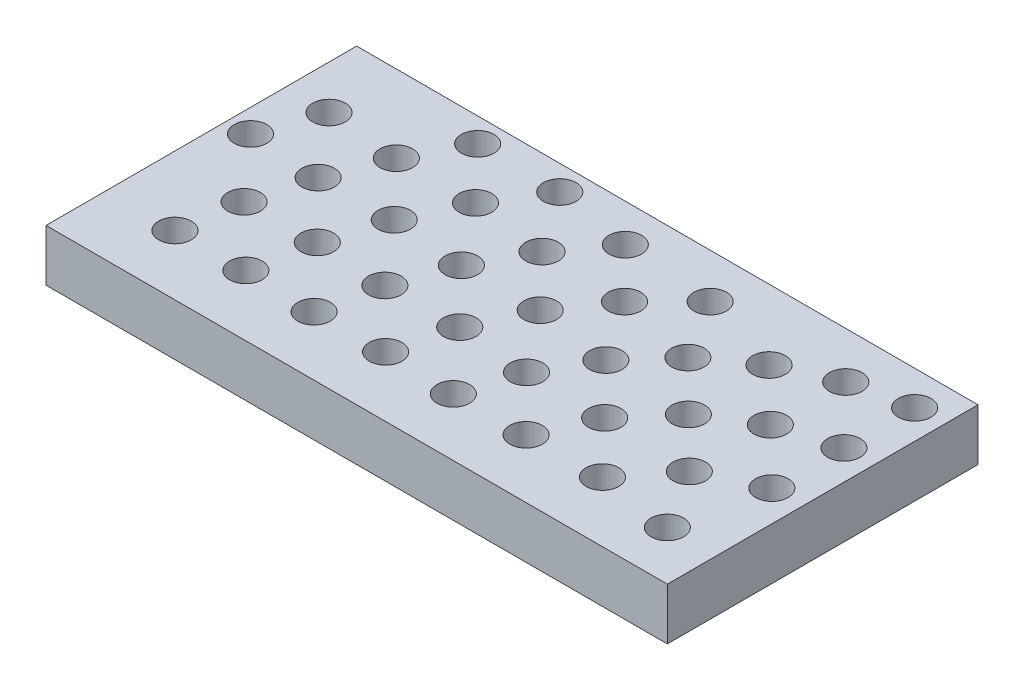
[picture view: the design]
ISO-10303-21;
HEADER;
FILE_DESCRIPTION(('STEP AP214'),'2;1');
FILE_NAME('part.step','',(''),(''),'','','');
FILE_SCHEMA(('AUTOMOTIVE_DESIGN { 1 0 10303 214 1 1 1 1 }'));
ENDSEC;
DATA;
#1=APPLICATION_CONTEXT('core data for automotive mechanical design processes');
#2=APPLICATION_PROTOCOL_DEFINITION('international standard','automotive_design',2000,#1);
#3=PRODUCT_CONTEXT('',#1,'mechanical');
#4=PRODUCT('Part','Part','',(#3));
#5=PRODUCT_RELATED_PRODUCT_CATEGORY('part','',(#4));
#6=PRODUCT_DEFINITION_FORMATION('','',#4);
#7=PRODUCT_DEFINITION_CONTEXT('part definition',#1,'design');
#8=PRODUCT_DEFINITION('design','',#6,#7);
#9=PRODUCT_DEFINITION_SHAPE('','',#8);
#10=(LENGTH_UNIT() NAMED_UNIT(*) SI_UNIT(.MILLI.,.METRE.));
#11=(NAMED_UNIT(*) PLANE_ANGLE_UNIT() SI_UNIT($,.RADIAN.));
#12=(NAMED_UNIT(*) SI_UNIT($,.STERADIAN.) SOLID_ANGLE_UNIT());
#13=UNCERTAINTY_MEASURE_WITH_UNIT(LENGTH_MEASURE(1.E-05),#10,'distance_accuracy_value','');
#14=(GEOMETRIC_REPRESENTATION_CONTEXT(3) GLOBAL_UNCERTAINTY_ASSIGNED_CONTEXT((#13)) GLOBAL_UNIT_ASSIGNED_CONTEXT((#10,
#11,#12)) REPRESENTATION_CONTEXT('',''));
#15=CARTESIAN_POINT('',(0.,0.,0.));
#16=DIRECTION('',(0.,0.,1.));
#17=DIRECTION('',(1.,0.,0.));
#18=AXIS2_PLACEMENT_3D('',#15,#16,#17);
#19=CARTESIAN_POINT('',(-76.2,12.7,-38.1));
#20=DIRECTION('',(1.,0.,0.));
#21=DIRECTION('',(0.,0.,-1.));
#22=AXIS2_PLACEMENT_3D('',#19,#20,#21);
#23=PLANE('',#22);
#24=DIRECTION('',(0.,0.,1.));
#25=VECTOR('',#24,1.);
#26=CARTESIAN_POINT('',(-76.2,0.,-38.1));
#27=LINE('',#26,#25);
#28=CARTESIAN_POINT('',(-76.2,0.,-38.1));
#29=VERTEX_POINT('',#28);
#30=CARTESIAN_POINT('',(-76.2,0.,38.1));
#31=VERTEX_POINT('',#30);
#32=EDGE_CURVE('E96',#29,#31,#27,.T.);
#33=ORIENTED_EDGE('',*,*,#32,.T.);
#34=DIRECTION('',(0.,-1.,0.));
#35=VECTOR('',#34,1.);
#36=CARTESIAN_POINT('',(-76.2,12.7,38.1));
#37=LINE('',#36,#35);
#38=CARTESIAN_POINT('',(-76.2,12.7,38.1));
#39=VERTEX_POINT('',#38);
#40=EDGE_CURVE('E12',#39,#31,#37,.T.);
#41=ORIENTED_EDGE('',*,*,#40,.F.);
#42=DIRECTION('',(0.,0.,1.));
#43=VECTOR('',#42,1.);
#44=CARTESIAN_POINT('',(-76.2,12.7,-38.1));
#45=LINE('',#44,#43);
#46=CARTESIAN_POINT('',(-76.2,12.7,-38.1));
#47=VERTEX_POINT('',#46);
#48=EDGE_CURVE('E84',#47,#39,#45,.T.);
#49=ORIENTED_EDGE('',*,*,#48,.F.);
#50=DIRECTION('',(0.,-1.,0.));
#51=VECTOR('',#50,1.);
#52=CARTESIAN_POINT('',(-76.2,12.7,-38.1));
#53=LINE('',#52,#51);
#54=EDGE_CURVE('E92',#47,#29,#53,.T.);
#55=ORIENTED_EDGE('',*,*,#54,.T.);
#56=EDGE_LOOP('',(#33,#41,#49,#55));
#57=FACE_BOUND('',#56,.T.);
#58=ADVANCED_FACE('F33',(#57),#23,.F.);
#59=CARTESIAN_POINT('',(-76.2,12.7,38.1));
#60=DIRECTION('',(0.,0.,-1.));
#61=DIRECTION('',(-1.,0.,0.));
#62=AXIS2_PLACEMENT_3D('',#59,#60,#61);
#63=PLANE('',#62);
#64=DIRECTION('',(1.,0.,0.));
#65=VECTOR('',#64,1.);
#66=CARTESIAN_POINT('',(-76.2,0.,38.1));
#67=LINE('',#66,#65);
#68=CARTESIAN_POINT('',(76.2,0.,38.1));
#69=VERTEX_POINT('',#68);
#70=EDGE_CURVE('E88',#31,#69,#67,.T.);
#71=ORIENTED_EDGE('',*,*,#70,.T.);
#72=DIRECTION('',(0.,-1.,0.));
#73=VECTOR('',#72,1.);
#74=CARTESIAN_POINT('',(76.2,12.7,38.1));
#75=LINE('',#74,#73);
#76=CARTESIAN_POINT('',(76.2,12.7,38.1));
#77=VERTEX_POINT('',#76);
#78=EDGE_CURVE('E41',#77,#69,#75,.T.);
#79=ORIENTED_EDGE('',*,*,#78,.F.);
#80=DIRECTION('',(1.,0.,0.));
#81=VECTOR('',#80,1.);
#82=CARTESIAN_POINT('',(-76.2,12.7,38.1));
#83=LINE('',#82,#81);
#84=EDGE_CURVE('E79',#39,#77,#83,.T.);
#85=ORIENTED_EDGE('',*,*,#84,.F.);
#86=ORIENTED_EDGE('',*,*,#40,.T.);
#87=EDGE_LOOP('',(#71,#79,#85,#86));
#88=FACE_BOUND('',#87,.T.);
#89=ADVANCED_FACE('F87',(#88),#63,.F.);
#90=CARTESIAN_POINT('',(76.2,12.7,-38.1));
#91=DIRECTION('',(-1.,0.,0.));
#92=DIRECTION('',(0.,0.,1.));
#93=AXIS2_PLACEMENT_3D('',#90,#91,#92);
#94=PLANE('',#93);
#95=DIRECTION('',(0.,0.,-1.));
#96=VECTOR('',#95,1.);
#97=CARTESIAN_POINT('',(76.2,0.,-38.1));
#98=LINE('',#97,#96);
#99=CARTESIAN_POINT('',(76.2,0.,-38.1));
#100=VERTEX_POINT('',#99);
#101=EDGE_CURVE('E66',#69,#100,#98,.T.);
#102=ORIENTED_EDGE('',*,*,#101,.T.);
#103=DIRECTION('',(0.,-1.,0.));
#104=VECTOR('',#103,1.);
#105=CARTESIAN_POINT('',(76.2,12.7,-38.1));
#106=LINE('',#105,#104);
#107=CARTESIAN_POINT('',(76.2,12.7,-38.1));
#108=VERTEX_POINT('',#107);
#109=EDGE_CURVE('E89',#108,#100,#106,.T.);
#110=ORIENTED_EDGE('',*,*,#109,.F.);
#111=DIRECTION('',(0.,0.,-1.));
#112=VECTOR('',#111,1.);
#113=CARTESIAN_POINT('',(76.2,12.7,-38.1));
#114=LINE('',#113,#112);
#115=EDGE_CURVE('E82',#77,#108,#114,.T.);
#116=ORIENTED_EDGE('',*,*,#115,.F.);
#117=ORIENTED_EDGE('',*,*,#78,.T.);
#118=EDGE_LOOP('',(#102,#110,#116,#117));
#119=FACE_BOUND('',#118,.T.);
#120=ADVANCED_FACE('F90',(#119),#94,.F.);
#121=CARTESIAN_POINT('',(-76.2,12.7,-38.1));
#122=DIRECTION('',(0.,0.,1.));
#123=DIRECTION('',(1.,0.,0.));
#124=AXIS2_PLACEMENT_3D('',#121,#122,#123);
#125=PLANE('',#124);
#126=DIRECTION('',(-1.,0.,0.));
#127=VECTOR('',#126,1.);
#128=CARTESIAN_POINT('',(-76.2,0.,-38.1));
#129=LINE('',#128,#127);
#130=EDGE_CURVE('E72',#100,#29,#129,.T.);
#131=ORIENTED_EDGE('',*,*,#130,.T.);
#132=ORIENTED_EDGE('',*,*,#54,.F.);
#133=DIRECTION('',(-1.,0.,0.));
#134=VECTOR('',#133,1.);
#135=CARTESIAN_POINT('',(-76.2,12.7,-38.1));
#136=LINE('',#135,#134);
#137=EDGE_CURVE('E49',#108,#47,#136,.T.);
#138=ORIENTED_EDGE('',*,*,#137,.F.);
#139=ORIENTED_EDGE('',*,*,#109,.T.);
#140=EDGE_LOOP('',(#131,#132,#138,#139));
#141=FACE_BOUND('',#140,.T.);
#142=ADVANCED_FACE('F104',(#141),#125,.F.);
#143=CARTESIAN_POINT('',(-76.2,12.7,38.1));
#144=DIRECTION('',(0.,1.,0.));
#145=DIRECTION('',(0.,0.,1.));
#146=AXIS2_PLACEMENT_3D('',#143,#144,#145);
#147=PLANE('',#146);
#148=CARTESIAN_POINT('',(-65.4765030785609,12.7,-20.5843290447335));
#149=DIRECTION('',(0.,1.,0.));
#150=DIRECTION('',(1.,0.,0.));
#151=AXIS2_PLACEMENT_3D('',#148,#149,#150);
#152=CIRCLE('',#151,4.);
#153=CARTESIAN_POINT('',(-61.4765030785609,12.7,-20.5843290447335));
#154=VERTEX_POINT('',#153);
#155=EDGE_CURVE('E332',#154,#154,#152,.T.);
#156=ORIENTED_EDGE('',*,*,#155,.F.);
#157=EDGE_LOOP('',(#156));
#158=FACE_BOUND('',#157,.T.);
#159=CARTESIAN_POINT('',(-70.546362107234,12.7,-6.41502227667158));
#160=DIRECTION('',(0.,1.,0.));
#161=DIRECTION('',(1.,0.,0.));
#162=AXIS2_PLACEMENT_3D('',#159,#160,#161);
#163=CIRCLE('',#162,4.);
#164=CARTESIAN_POINT('',(-66.546362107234,12.7,-6.41502227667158));
#165=VERTEX_POINT('',#164);
#166=EDGE_CURVE('E326',#165,#165,#163,.T.);
#167=ORIENTED_EDGE('',*,*,#166,.F.);
#168=EDGE_LOOP('',(#167));
#169=FACE_BOUND('',#168,.T.);
#170=CARTESIAN_POINT('',(-40.5988048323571,12.7,-32.175509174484));
#171=DIRECTION('',(0.,1.,0.));
#172=DIRECTION('',(1.,0.,0.));
#173=AXIS2_PLACEMENT_3D('',#170,#171,#172);
#174=CIRCLE('',#173,4.);
#175=CARTESIAN_POINT('',(-36.5988048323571,12.7,-32.175509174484));
#176=VERTEX_POINT('',#175);
#177=EDGE_CURVE('E320',#176,#176,#174,.T.);
#178=ORIENTED_EDGE('',*,*,#177,.F.);
#179=EDGE_LOOP('',(#178));
#180=FACE_BOUND('',#179,.T.);
#181=CARTESIAN_POINT('',(-47.5122443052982,12.7,-19.13537899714));
#182=DIRECTION('',(0.,1.,0.));
#183=DIRECTION('',(1.,0.,0.));
#184=AXIS2_PLACEMENT_3D('',#181,#182,#183);
#185=CIRCLE('',#184,4.);
#186=CARTESIAN_POINT('',(-43.5122443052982,12.7,-19.13537899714));
#187=VERTEX_POINT('',#186);
#188=EDGE_CURVE('E314',#187,#187,#185,.T.);
#189=ORIENTED_EDGE('',*,*,#188,.F.);
#190=EDGE_LOOP('',(#189));
#191=FACE_BOUND('',#190,.T.);
#192=CARTESIAN_POINT('',(-52.9752708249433,12.7,-5.42421633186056));
#193=DIRECTION('',(0.,1.,0.));
#194=DIRECTION('',(1.,0.,0.));
#195=AXIS2_PLACEMENT_3D('',#192,#193,#194);
#196=CIRCLE('',#195,4.);
#197=CARTESIAN_POINT('',(-48.9752708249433,12.7,-5.42421633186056));
#198=VERTEX_POINT('',#197);
#199=EDGE_CURVE('E308',#198,#198,#196,.T.);
#200=ORIENTED_EDGE('',*,*,#199,.F.);
#201=EDGE_LOOP('',(#200));
#202=FACE_BOUND('',#201,.T.);
#203=CARTESIAN_POINT('',(-56.9238354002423,12.7,8.79722797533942));
#204=DIRECTION('',(0.,1.,0.));
#205=DIRECTION('',(1.,0.,0.));
#206=AXIS2_PLACEMENT_3D('',#203,#204,#205);
#207=CIRCLE('',#206,4.);
#208=CARTESIAN_POINT('',(-52.9238354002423,12.7,8.79722797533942));
#209=VERTEX_POINT('',#208);
#210=EDGE_CURVE('E302',#209,#209,#207,.T.);
#211=ORIENTED_EDGE('',*,*,#210,.F.);
#212=EDGE_LOOP('',(#211));
#213=FACE_BOUND('',#212,.T.);
#214=CARTESIAN_POINT('',(-59.3116447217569,12.7,23.3622204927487));
#215=DIRECTION('',(0.,1.,0.));
#216=DIRECTION('',(1.,0.,0.));
#217=AXIS2_PLACEMENT_3D('',#214,#215,#216);
#218=CIRCLE('',#217,4.);
#219=CARTESIAN_POINT('',(-55.3116447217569,12.7,23.3622204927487));
#220=VERTEX_POINT('',#219);
#221=EDGE_CURVE('E296',#220,#220,#218,.T.);
#222=ORIENTED_EDGE('',*,*,#221,.F.);
#223=EDGE_LOOP('',(#222));
#224=FACE_BOUND('',#223,.T.);
#225=CARTESIAN_POINT('',(-20.2929664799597,12.7,-32.0062438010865));
#226=DIRECTION('',(0.,1.,0.));
#227=DIRECTION('',(1.,0.,0.));
#228=AXIS2_PLACEMENT_3D('',#225,#226,#227);
#229=CIRCLE('',#228,4.);
#230=CARTESIAN_POINT('',(-16.2929664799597,12.7,-32.0062438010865));
#231=VERTEX_POINT('',#230);
#232=EDGE_CURVE('E290',#231,#231,#229,.T.);
#233=ORIENTED_EDGE('',*,*,#232,.F.);
#234=EDGE_LOOP('',(#233));
#235=FACE_BOUND('',#234,.T.);
#236=CARTESIAN_POINT('',(-28.3187328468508,12.7,-19.3596596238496));
#237=DIRECTION('',(0.,1.,0.));
#238=DIRECTION('',(1.,0.,0.));
#239=AXIS2_PLACEMENT_3D('',#236,#237,#238);
#240=CIRCLE('',#239,4.);
#241=CARTESIAN_POINT('',(-24.3187328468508,12.7,-19.3596596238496));
#242=VERTEX_POINT('',#241);
#243=EDGE_CURVE('E284',#242,#242,#240,.T.);
#244=ORIENTED_EDGE('',*,*,#243,.F.);
#245=EDGE_LOOP('',(#244));
#246=FACE_BOUND('',#245,.T.);
#247=CARTESIAN_POINT('',(-34.6961763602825,12.7,-5.80690228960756));
#248=DIRECTION('',(0.,1.,0.));
#249=DIRECTION('',(1.,0.,0.));
#250=AXIS2_PLACEMENT_3D('',#247,#248,#249);
#251=CIRCLE('',#250,4.);
#252=CARTESIAN_POINT('',(-30.6961763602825,12.7,-5.80690228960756));
#253=VERTEX_POINT('',#252);
#254=EDGE_CURVE('E278',#253,#253,#251,.T.);
#255=ORIENTED_EDGE('',*,*,#254,.F.);
#256=EDGE_LOOP('',(#255));
#257=FACE_BOUND('',#256,.T.);
#258=CARTESIAN_POINT('',(-39.3247209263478,12.7,8.4382931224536));
#259=DIRECTION('',(0.,1.,0.));
#260=DIRECTION('',(1.,0.,0.));
#261=AXIS2_PLACEMENT_3D('',#258,#259,#260);
#262=CIRCLE('',#261,4.);
#263=CARTESIAN_POINT('',(-35.3247209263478,12.7,8.4382931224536));
#264=VERTEX_POINT('',#263);
#265=EDGE_CURVE('E272',#264,#264,#262,.T.);
#266=ORIENTED_EDGE('',*,*,#265,.F.);
#267=EDGE_LOOP('',(#266));
#268=FACE_BOUND('',#267,.T.);
#269=CARTESIAN_POINT('',(-1.06256734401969,12.7,-28.8483957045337));
#270=DIRECTION('',(0.,1.,0.));
#271=DIRECTION('',(1.,0.,0.));
#272=AXIS2_PLACEMENT_3D('',#269,#270,#271);
#273=CIRCLE('',#272,4.);
#274=CARTESIAN_POINT('',(2.93743265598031,12.7,-28.8483957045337));
#275=VERTEX_POINT('',#274);
#276=EDGE_CURVE('E266',#275,#275,#273,.T.);
#277=ORIENTED_EDGE('',*,*,#276,.F.);
#278=EDGE_LOOP('',(#277));
#279=FACE_BOUND('',#278,.T.);
#280=CARTESIAN_POINT('',(-42.1313716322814,12.7,23.1512713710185));
#281=DIRECTION('',(0.,1.,0.));
#282=DIRECTION('',(1.,0.,0.));
#283=AXIS2_PLACEMENT_3D('',#280,#281,#282);
#284=CIRCLE('',#283,4.);
#285=CARTESIAN_POINT('',(-38.1313716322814,12.7,23.1512713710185));
#286=VERTEX_POINT('',#285);
#287=EDGE_CURVE('E260',#286,#286,#284,.T.);
#288=ORIENTED_EDGE('',*,*,#287,.F.);
#289=EDGE_LOOP('',(#288));
#290=FACE_BOUND('',#289,.T.);
#291=CARTESIAN_POINT('',(-9.80389591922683,12.7,-17.1713477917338));
#292=DIRECTION('',(0.,1.,0.));
#293=DIRECTION('',(1.,0.,0.));
#294=AXIS2_PLACEMENT_3D('',#291,#292,#293);
#295=CIRCLE('',#294,4.);
#296=CARTESIAN_POINT('',(-5.80389591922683,12.7,-17.1713477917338));
#297=VERTEX_POINT('',#296);
#298=EDGE_CURVE('E254',#297,#297,#295,.T.);
#299=ORIENTED_EDGE('',*,*,#298,.F.);
#300=EDGE_LOOP('',(#299));
#301=FACE_BOUND('',#300,.T.);
#302=CARTESIAN_POINT('',(-16.7944331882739,12.7,-4.36913462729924));
#303=DIRECTION('',(0.,1.,0.));
#304=DIRECTION('',(1.,0.,0.));
#305=AXIS2_PLACEMENT_3D('',#302,#303,#304);
#306=CIRCLE('',#305,4.);
#307=CARTESIAN_POINT('',(-12.7944331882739,12.7,-4.36913462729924));
#308=VERTEX_POINT('',#307);
#309=EDGE_CURVE('E248',#308,#308,#306,.T.);
#310=ORIENTED_EDGE('',*,*,#309,.F.);
#311=EDGE_LOOP('',(#310));
#312=FACE_BOUND('',#311,.T.);
#313=CARTESIAN_POINT('',(-21.8918719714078,12.7,9.29762764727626));
#314=DIRECTION('',(0.,1.,0.));
#315=DIRECTION('',(1.,0.,0.));
#316=AXIS2_PLACEMENT_3D('',#313,#314,#315);
#317=CIRCLE('',#316,4.);
#318=CARTESIAN_POINT('',(-17.8918719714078,12.7,9.29762764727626));
#319=VERTEX_POINT('',#318);
#320=EDGE_CURVE('E242',#319,#319,#317,.T.);
#321=ORIENTED_EDGE('',*,*,#320,.F.);
#322=EDGE_LOOP('',(#321));
#323=FACE_BOUND('',#322,.T.);
#324=CARTESIAN_POINT('',(-24.9924431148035,12.7,23.5507231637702));
#325=DIRECTION('',(0.,1.,0.));
#326=DIRECTION('',(1.,0.,0.));
#327=AXIS2_PLACEMENT_3D('',#324,#325,#326);
#328=CIRCLE('',#327,4.);
#329=CARTESIAN_POINT('',(-20.9924431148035,12.7,23.5507231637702));
#330=VERTEX_POINT('',#329);
#331=EDGE_CURVE('E236',#330,#330,#328,.T.);
#332=ORIENTED_EDGE('',*,*,#331,.F.);
#333=EDGE_LOOP('',(#332));
#334=FACE_BOUND('',#333,.T.);
#335=CARTESIAN_POINT('',(21.4382302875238,12.7,-27.1625357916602));
#336=DIRECTION('',(0.,1.,0.));
#337=DIRECTION('',(1.,0.,0.));
#338=AXIS2_PLACEMENT_3D('',#335,#336,#337);
#339=CIRCLE('',#338,4.);
#340=CARTESIAN_POINT('',(25.4382302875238,12.7,-27.1625357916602));
#341=VERTEX_POINT('',#340);
#342=EDGE_CURVE('E230',#341,#341,#339,.T.);
#343=ORIENTED_EDGE('',*,*,#342,.F.);
#344=EDGE_LOOP('',(#343));
#345=FACE_BOUND('',#344,.T.);
#346=CARTESIAN_POINT('',(10.9374642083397,12.7,-16.6617697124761));
#347=DIRECTION('',(0.,1.,0.));
#348=DIRECTION('',(1.,0.,0.));
#349=AXIS2_PLACEMENT_3D('',#346,#347,#348);
#350=CIRCLE('',#349,4.);
#351=CARTESIAN_POINT('',(14.9374642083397,12.7,-16.6617697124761));
#352=VERTEX_POINT('',#351);
#353=EDGE_CURVE('E224',#352,#352,#350,.T.);
#354=ORIENTED_EDGE('',*,*,#353,.F.);
#355=EDGE_LOOP('',(#354));
#356=FACE_BOUND('',#355,.T.);
#357=CARTESIAN_POINT('',(69.075825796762,12.7,-29.6819898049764));
#358=DIRECTION('',(0.,1.,0.));
#359=DIRECTION('',(1.,0.,0.));
#360=AXIS2_PLACEMENT_3D('',#357,#358,#359);
#361=CIRCLE('',#360,4.);
#362=CARTESIAN_POINT('',(73.0758257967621,12.7,-29.6819898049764));
#363=VERTEX_POINT('',#362);
#364=EDGE_CURVE('E218',#363,#363,#361,.T.);
#365=ORIENTED_EDGE('',*,*,#364,.F.);
#366=EDGE_LOOP('',(#365));
#367=FACE_BOUND('',#366,.T.);
#368=CARTESIAN_POINT('',(2.41966725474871,12.7,-4.49709497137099));
#369=DIRECTION('',(0.,1.,0.));
#370=DIRECTION('',(1.,0.,0.));
#371=AXIS2_PLACEMENT_3D('',#368,#369,#370);
#372=CIRCLE('',#371,4.);
#373=CARTESIAN_POINT('',(6.41966725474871,12.7,-4.49709497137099));
#374=VERTEX_POINT('',#373);
#375=EDGE_CURVE('E212',#374,#374,#372,.T.);
#376=ORIENTED_EDGE('',*,*,#375,.F.);
#377=EDGE_LOOP('',(#376));
#378=FACE_BOUND('',#377,.T.);
#379=CARTESIAN_POINT('',(55.1388379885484,12.7,-26.7195915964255));
#380=DIRECTION('',(0.,1.,0.));
#381=DIRECTION('',(1.,0.,0.));
#382=AXIS2_PLACEMENT_3D('',#379,#380,#381);
#383=CIRCLE('',#382,4.);
#384=CARTESIAN_POINT('',(59.1388379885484,12.7,-26.7195915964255));
#385=VERTEX_POINT('',#384);
#386=EDGE_CURVE('E206',#385,#385,#383,.T.);
#387=ORIENTED_EDGE('',*,*,#386,.F.);
#388=EDGE_LOOP('',(#387));
#389=FACE_BOUND('',#388,.T.);
#390=CARTESIAN_POINT('',(-3.85635162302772,12.7,8.96187094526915));
#391=DIRECTION('',(0.,1.,0.));
#392=DIRECTION('',(1.,0.,0.));
#393=AXIS2_PLACEMENT_3D('',#390,#391,#392);
#394=CIRCLE('',#393,4.);
#395=CARTESIAN_POINT('',(0.143648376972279,12.7,8.96187094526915));
#396=VERTEX_POINT('',#395);
#397=EDGE_CURVE('E200',#396,#396,#394,.T.);
#398=ORIENTED_EDGE('',*,*,#397,.F.);
#399=EDGE_LOOP('',(#398));
#400=FACE_BOUND('',#399,.T.);
#401=CARTESIAN_POINT('',(42.1223240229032,12.7,-20.924266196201));
#402=DIRECTION('',(0.,1.,0.));
#403=DIRECTION('',(1.,0.,0.));
#404=AXIS2_PLACEMENT_3D('',#401,#402,#403);
#405=CIRCLE('',#404,4.);
#406=CARTESIAN_POINT('',(46.1223240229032,12.7,-20.924266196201));
#407=VERTEX_POINT('',#406);
#408=EDGE_CURVE('E194',#407,#407,#405,.T.);
#409=ORIENTED_EDGE('',*,*,#408,.F.);
#410=EDGE_LOOP('',(#409));
#411=FACE_BOUND('',#410,.T.);
#412=CARTESIAN_POINT('',(-7.699898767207,12.7,23.3061841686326));
#413=DIRECTION('',(0.,1.,0.));
#414=DIRECTION('',(1.,0.,0.));
#415=AXIS2_PLACEMENT_3D('',#412,#413,#414);
#416=CIRCLE('',#415,4.);
#417=CARTESIAN_POINT('',(-3.699898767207,12.7,23.3061841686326));
#418=VERTEX_POINT('',#417);
#419=EDGE_CURVE('E188',#418,#418,#416,.T.);
#420=ORIENTED_EDGE('',*,*,#419,.F.);
#421=EDGE_LOOP('',(#420));
#422=FACE_BOUND('',#421,.T.);
#423=CARTESIAN_POINT('',(30.5951680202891,12.7,-12.5492971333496));
#424=DIRECTION('',(0.,1.,0.));
#425=DIRECTION('',(1.,0.,0.));
#426=AXIS2_PLACEMENT_3D('',#423,#424,#425);
#427=CIRCLE('',#426,4.);
#428=CARTESIAN_POINT('',(34.5951680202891,12.7,-12.5492971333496));
#429=VERTEX_POINT('',#428);
#430=EDGE_CURVE('E182',#429,#429,#427,.T.);
#431=ORIENTED_EDGE('',*,*,#430,.F.);
#432=EDGE_LOOP('',(#431));
#433=FACE_BOUND('',#432,.T.);
#434=CARTESIAN_POINT('',(21.0611620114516,12.7,-1.96071074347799));
#435=DIRECTION('',(0.,1.,0.));
#436=DIRECTION('',(1.,0.,0.));
#437=AXIS2_PLACEMENT_3D('',#434,#435,#436);
#438=CIRCLE('',#437,4.);
#439=CARTESIAN_POINT('',(25.0611620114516,12.7,-1.96071074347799));
#440=VERTEX_POINT('',#439);
#441=EDGE_CURVE('E176',#440,#440,#438,.T.);
#442=ORIENTED_EDGE('',*,*,#441,.F.);
#443=EDGE_LOOP('',(#442));
#444=FACE_BOUND('',#443,.T.);
#445=CARTESIAN_POINT('',(13.9369878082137,12.7,10.3787209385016));
#446=DIRECTION('',(0.,1.,0.));
#447=DIRECTION('',(1.,0.,0.));
#448=AXIS2_PLACEMENT_3D('',#445,#446,#447);
#449=CIRCLE('',#448,4.);
#450=CARTESIAN_POINT('',(17.9369878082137,12.7,10.3787209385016));
#451=VERTEX_POINT('',#450);
#452=EDGE_CURVE('E170',#451,#451,#449,.T.);
#453=ORIENTED_EDGE('',*,*,#452,.F.);
#454=EDGE_LOOP('',(#453));
#455=FACE_BOUND('',#454,.T.);
#456=CARTESIAN_POINT('',(9.53400600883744,12.7,23.9297055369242));
#457=DIRECTION('',(0.,1.,0.));
#458=DIRECTION('',(1.,0.,0.));
#459=AXIS2_PLACEMENT_3D('',#456,#457,#458);
#460=CIRCLE('',#459,4.);
#461=CARTESIAN_POINT('',(13.5340060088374,12.7,23.9297055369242));
#462=VERTEX_POINT('',#461);
#463=EDGE_CURVE('E164',#462,#462,#460,.T.);
#464=ORIENTED_EDGE('',*,*,#463,.F.);
#465=EDGE_LOOP('',(#464));
#466=FACE_BOUND('',#465,.T.);
#467=CARTESIAN_POINT('',(68.9253615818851,12.7,-12.4962215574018));
#468=DIRECTION('',(0.,1.,0.));
#469=DIRECTION('',(1.,0.,0.));
#470=AXIS2_PLACEMENT_3D('',#467,#468,#469);
#471=CIRCLE('',#470,4.);
#472=CARTESIAN_POINT('',(72.9253615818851,12.7,-12.4962215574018));
#473=VERTEX_POINT('',#472);
#474=EDGE_CURVE('E158',#473,#473,#471,.T.);
#475=ORIENTED_EDGE('',*,*,#474,.F.);
#476=EDGE_LOOP('',(#475));
#477=FACE_BOUND('',#476,.T.);
#478=CARTESIAN_POINT('',(54.9654326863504,12.7,-8.39721659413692));
#479=DIRECTION('',(0.,1.,0.));
#480=DIRECTION('',(1.,0.,0.));
#481=AXIS2_PLACEMENT_3D('',#478,#479,#480);
#482=CIRCLE('',#481,4.);
#483=CARTESIAN_POINT('',(58.9654326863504,12.7,-8.39721659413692));
#484=VERTEX_POINT('',#483);
#485=EDGE_CURVE('E152',#484,#484,#482,.T.);
#486=ORIENTED_EDGE('',*,*,#485,.F.);
#487=EDGE_LOOP('',(#486));
#488=FACE_BOUND('',#487,.T.);
#489=CARTESIAN_POINT('',(42.7258021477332,12.7,-0.531283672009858));
#490=DIRECTION('',(0.,1.,0.));
#491=DIRECTION('',(1.,0.,0.));
#492=AXIS2_PLACEMENT_3D('',#489,#490,#491);
#493=CIRCLE('',#492,4.);
#494=CARTESIAN_POINT('',(46.7258021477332,12.7,-0.531283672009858));
#495=VERTEX_POINT('',#494);
#496=EDGE_CURVE('E146',#495,#495,#493,.T.);
#497=ORIENTED_EDGE('',*,*,#496,.F.);
#498=EDGE_LOOP('',(#497));
#499=FACE_BOUND('',#498,.T.);
#500=CARTESIAN_POINT('',(33.1980520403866,12.7,10.4643261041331));
#501=DIRECTION('',(0.,1.,0.));
#502=DIRECTION('',(1.,0.,0.));
#503=AXIS2_PLACEMENT_3D('',#500,#501,#502);
#504=CIRCLE('',#503,4.);
#505=CARTESIAN_POINT('',(37.1980520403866,12.7,10.4643261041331));
#506=VERTEX_POINT('',#505);
#507=EDGE_CURVE('E140',#506,#506,#504,.T.);
#508=ORIENTED_EDGE('',*,*,#507,.F.);
#509=EDGE_LOOP('',(#508));
#510=FACE_BOUND('',#509,.T.);
#511=CARTESIAN_POINT('',(27.1540640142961,12.7,23.6988138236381));
#512=DIRECTION('',(0.,1.,0.));
#513=DIRECTION('',(1.,0.,0.));
#514=AXIS2_PLACEMENT_3D('',#511,#512,#513);
#515=CIRCLE('',#514,4.);
#516=CARTESIAN_POINT('',(31.1540640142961,12.7,23.6988138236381));
#517=VERTEX_POINT('',#516);
#518=EDGE_CURVE('E134',#517,#517,#515,.T.);
#519=ORIENTED_EDGE('',*,*,#518,.F.);
#520=EDGE_LOOP('',(#519));
#521=FACE_BOUND('',#520,.T.);
#522=CARTESIAN_POINT('',(68.6170037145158,12.7,4.87672250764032));
#523=DIRECTION('',(0.,1.,0.));
#524=DIRECTION('',(1.,0.,0.));
#525=AXIS2_PLACEMENT_3D('',#522,#523,#524);
#526=CIRCLE('',#525,4.);
#527=CARTESIAN_POINT('',(72.6170037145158,12.7,4.87672250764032));
#528=VERTEX_POINT('',#527);
#529=EDGE_CURVE('E128',#528,#528,#526,.T.);
#530=ORIENTED_EDGE('',*,*,#529,.F.);
#531=EDGE_LOOP('',(#530));
#532=FACE_BOUND('',#531,.T.);
#533=CARTESIAN_POINT('',(54.9529165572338,12.7,11.4570000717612));
#534=DIRECTION('',(0.,1.,0.));
#535=DIRECTION('',(1.,0.,0.));
#536=AXIS2_PLACEMENT_3D('',#533,#534,#535);
#537=CIRCLE('',#536,4.);
#538=CARTESIAN_POINT('',(58.9529165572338,12.7,11.4570000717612));
#539=VERTEX_POINT('',#538);
#540=EDGE_CURVE('E122',#539,#539,#537,.T.);
#541=ORIENTED_EDGE('',*,*,#540,.F.);
#542=EDGE_LOOP('',(#541));
#543=FACE_BOUND('',#542,.T.);
#544=CARTESIAN_POINT('',(45.4970748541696,12.7,23.3142505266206));
#545=DIRECTION('',(0.,1.,0.));
#546=DIRECTION('',(1.,0.,0.));
#547=AXIS2_PLACEMENT_3D('',#544,#545,#546);
#548=CIRCLE('',#547,4.);
#549=CARTESIAN_POINT('',(49.4970748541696,12.7,23.3142505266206));
#550=VERTEX_POINT('',#549);
#551=EDGE_CURVE('E116',#550,#550,#548,.T.);
#552=ORIENTED_EDGE('',*,*,#551,.F.);
#553=EDGE_LOOP('',(#552));
#554=FACE_BOUND('',#553,.T.);
#555=CARTESIAN_POINT('',(64.1517221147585,12.7,26.0517221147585));
#556=DIRECTION('',(0.,1.,0.));
#557=DIRECTION('',(1.,0.,0.));
#558=AXIS2_PLACEMENT_3D('',#555,#556,#557);
#559=CIRCLE('',#558,4.);
#560=CARTESIAN_POINT('',(68.1517221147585,12.7,26.0517221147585));
#561=VERTEX_POINT('',#560);
#562=EDGE_CURVE('E110',#561,#561,#559,.T.);
#563=ORIENTED_EDGE('',*,*,#562,.F.);
#564=EDGE_LOOP('',(#563));
#565=FACE_BOUND('',#564,.T.);
#566=ORIENTED_EDGE('',*,*,#48,.T.);
#567=ORIENTED_EDGE('',*,*,#84,.T.);
#568=ORIENTED_EDGE('',*,*,#115,.T.);
#569=ORIENTED_EDGE('',*,*,#137,.T.);
#570=EDGE_LOOP('',(#566,#567,#568,#569));
#571=FACE_BOUND('',#570,.T.);
#572=ADVANCED_FACE('F80',(#158,#169,#180,#191,#202,#213,#224,#235,#246,#257,#268,#279,#290,#301,
#312,#323,#334,#345,#356,#367,#378,#389,#400,#411,#422,#433,#444,#455,#466,#477,#488,#499,#510,
#521,#532,#543,#554,#565,#571),#147,.T.);
#573=CARTESIAN_POINT('',(-76.2,0.,38.1));
#574=DIRECTION('',(0.,1.,0.));
#575=DIRECTION('',(0.,0.,1.));
#576=AXIS2_PLACEMENT_3D('',#573,#574,#575);
#577=PLANE('',#576);
#578=CARTESIAN_POINT('',(-65.4765030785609,0.,-20.5843290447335));
#579=DIRECTION('',(0.,1.,0.));
#580=DIRECTION('',(1.,0.,0.));
#581=AXIS2_PLACEMENT_3D('',#578,#579,#580);
#582=CIRCLE('',#581,4.);
#583=CARTESIAN_POINT('',(-61.4765030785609,0.,-20.5843290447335));
#584=VERTEX_POINT('',#583);
#585=EDGE_CURVE('E329',#584,#584,#582,.T.);
#586=ORIENTED_EDGE('',*,*,#585,.T.);
#587=EDGE_LOOP('',(#586));
#588=FACE_BOUND('',#587,.T.);
#589=CARTESIAN_POINT('',(-70.546362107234,0.,-6.41502227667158));
#590=DIRECTION('',(0.,1.,0.));
#591=DIRECTION('',(1.,0.,0.));
#592=AXIS2_PLACEMENT_3D('',#589,#590,#591);
#593=CIRCLE('',#592,4.);
#594=CARTESIAN_POINT('',(-66.546362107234,0.,-6.41502227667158));
#595=VERTEX_POINT('',#594);
#596=EDGE_CURVE('E323',#595,#595,#593,.T.);
#597=ORIENTED_EDGE('',*,*,#596,.T.);
#598=EDGE_LOOP('',(#597));
#599=FACE_BOUND('',#598,.T.);
#600=CARTESIAN_POINT('',(-40.5988048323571,0.,-32.175509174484));
#601=DIRECTION('',(0.,1.,0.));
#602=DIRECTION('',(1.,0.,0.));
#603=AXIS2_PLACEMENT_3D('',#600,#601,#602);
#604=CIRCLE('',#603,4.);
#605=CARTESIAN_POINT('',(-36.5988048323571,0.,-32.175509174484));
#606=VERTEX_POINT('',#605);
#607=EDGE_CURVE('E317',#606,#606,#604,.T.);
#608=ORIENTED_EDGE('',*,*,#607,.T.);
#609=EDGE_LOOP('',(#608));
#610=FACE_BOUND('',#609,.T.);
#611=CARTESIAN_POINT('',(-47.5122443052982,0.,-19.13537899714));
#612=DIRECTION('',(0.,1.,0.));
#613=DIRECTION('',(1.,0.,0.));
#614=AXIS2_PLACEMENT_3D('',#611,#612,#613);
#615=CIRCLE('',#614,4.);
#616=CARTESIAN_POINT('',(-43.5122443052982,0.,-19.13537899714));
#617=VERTEX_POINT('',#616);
#618=EDGE_CURVE('E311',#617,#617,#615,.T.);
#619=ORIENTED_EDGE('',*,*,#618,.T.);
#620=EDGE_LOOP('',(#619));
#621=FACE_BOUND('',#620,.T.);
#622=CARTESIAN_POINT('',(-52.9752708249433,0.,-5.42421633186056));
#623=DIRECTION('',(0.,1.,0.));
#624=DIRECTION('',(1.,0.,0.));
#625=AXIS2_PLACEMENT_3D('',#622,#623,#624);
#626=CIRCLE('',#625,4.);
#627=CARTESIAN_POINT('',(-48.9752708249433,0.,-5.42421633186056));
#628=VERTEX_POINT('',#627);
#629=EDGE_CURVE('E305',#628,#628,#626,.T.);
#630=ORIENTED_EDGE('',*,*,#629,.T.);
#631=EDGE_LOOP('',(#630));
#632=FACE_BOUND('',#631,.T.);
#633=CARTESIAN_POINT('',(-56.9238354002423,0.,8.79722797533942));
#634=DIRECTION('',(0.,1.,0.));
#635=DIRECTION('',(1.,0.,0.));
#636=AXIS2_PLACEMENT_3D('',#633,#634,#635);
#637=CIRCLE('',#636,4.);
#638=CARTESIAN_POINT('',(-52.9238354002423,0.,8.79722797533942));
#639=VERTEX_POINT('',#638);
#640=EDGE_CURVE('E299',#639,#639,#637,.T.);
#641=ORIENTED_EDGE('',*,*,#640,.T.);
#642=EDGE_LOOP('',(#641));
#643=FACE_BOUND('',#642,.T.);
#644=CARTESIAN_POINT('',(-59.3116447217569,0.,23.3622204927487));
#645=DIRECTION('',(0.,1.,0.));
#646=DIRECTION('',(1.,0.,0.));
#647=AXIS2_PLACEMENT_3D('',#644,#645,#646);
#648=CIRCLE('',#647,4.);
#649=CARTESIAN_POINT('',(-55.3116447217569,0.,23.3622204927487));
#650=VERTEX_POINT('',#649);
#651=EDGE_CURVE('E293',#650,#650,#648,.T.);
#652=ORIENTED_EDGE('',*,*,#651,.T.);
#653=EDGE_LOOP('',(#652));
#654=FACE_BOUND('',#653,.T.);
#655=CARTESIAN_POINT('',(-20.2929664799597,0.,-32.0062438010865));
#656=DIRECTION('',(0.,1.,0.));
#657=DIRECTION('',(1.,0.,0.));
#658=AXIS2_PLACEMENT_3D('',#655,#656,#657);
#659=CIRCLE('',#658,4.);
#660=CARTESIAN_POINT('',(-16.2929664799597,0.,-32.0062438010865));
#661=VERTEX_POINT('',#660);
#662=EDGE_CURVE('E287',#661,#661,#659,.T.);
#663=ORIENTED_EDGE('',*,*,#662,.T.);
#664=EDGE_LOOP('',(#663));
#665=FACE_BOUND('',#664,.T.);
#666=CARTESIAN_POINT('',(-28.3187328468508,0.,-19.3596596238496));
#667=DIRECTION('',(0.,1.,0.));
#668=DIRECTION('',(1.,0.,0.));
#669=AXIS2_PLACEMENT_3D('',#666,#667,#668);
#670=CIRCLE('',#669,4.);
#671=CARTESIAN_POINT('',(-24.3187328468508,0.,-19.3596596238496));
#672=VERTEX_POINT('',#671);
#673=EDGE_CURVE('E281',#672,#672,#670,.T.);
#674=ORIENTED_EDGE('',*,*,#673,.T.);
#675=EDGE_LOOP('',(#674));
#676=FACE_BOUND('',#675,.T.);
#677=CARTESIAN_POINT('',(-34.6961763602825,0.,-5.80690228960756));
#678=DIRECTION('',(0.,1.,0.));
#679=DIRECTION('',(1.,0.,0.));
#680=AXIS2_PLACEMENT_3D('',#677,#678,#679);
#681=CIRCLE('',#680,4.);
#682=CARTESIAN_POINT('',(-30.6961763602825,0.,-5.80690228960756));
#683=VERTEX_POINT('',#682);
#684=EDGE_CURVE('E275',#683,#683,#681,.T.);
#685=ORIENTED_EDGE('',*,*,#684,.T.);
#686=EDGE_LOOP('',(#685));
#687=FACE_BOUND('',#686,.T.);
#688=CARTESIAN_POINT('',(-39.3247209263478,0.,8.4382931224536));
#689=DIRECTION('',(0.,1.,0.));
#690=DIRECTION('',(1.,0.,0.));
#691=AXIS2_PLACEMENT_3D('',#688,#689,#690);
#692=CIRCLE('',#691,4.);
#693=CARTESIAN_POINT('',(-35.3247209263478,0.,8.4382931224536));
#694=VERTEX_POINT('',#693);
#695=EDGE_CURVE('E269',#694,#694,#692,.T.);
#696=ORIENTED_EDGE('',*,*,#695,.T.);
#697=EDGE_LOOP('',(#696));
#698=FACE_BOUND('',#697,.T.);
#699=CARTESIAN_POINT('',(-1.06256734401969,0.,-28.8483957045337));
#700=DIRECTION('',(0.,1.,0.));
#701=DIRECTION('',(1.,0.,0.));
#702=AXIS2_PLACEMENT_3D('',#699,#700,#701);
#703=CIRCLE('',#702,4.);
#704=CARTESIAN_POINT('',(2.93743265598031,0.,-28.8483957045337));
#705=VERTEX_POINT('',#704);
#706=EDGE_CURVE('E263',#705,#705,#703,.T.);
#707=ORIENTED_EDGE('',*,*,#706,.T.);
#708=EDGE_LOOP('',(#707));
#709=FACE_BOUND('',#708,.T.);
#710=CARTESIAN_POINT('',(-42.1313716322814,0.,23.1512713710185));
#711=DIRECTION('',(0.,1.,0.));
#712=DIRECTION('',(1.,0.,0.));
#713=AXIS2_PLACEMENT_3D('',#710,#711,#712);
#714=CIRCLE('',#713,4.);
#715=CARTESIAN_POINT('',(-38.1313716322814,0.,23.1512713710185));
#716=VERTEX_POINT('',#715);
#717=EDGE_CURVE('E257',#716,#716,#714,.T.);
#718=ORIENTED_EDGE('',*,*,#717,.T.);
#719=EDGE_LOOP('',(#718));
#720=FACE_BOUND('',#719,.T.);
#721=CARTESIAN_POINT('',(-9.80389591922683,0.,-17.1713477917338));
#722=DIRECTION('',(0.,1.,0.));
#723=DIRECTION('',(1.,0.,0.));
#724=AXIS2_PLACEMENT_3D('',#721,#722,#723);
#725=CIRCLE('',#724,4.);
#726=CARTESIAN_POINT('',(-5.80389591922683,0.,-17.1713477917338));
#727=VERTEX_POINT('',#726);
#728=EDGE_CURVE('E251',#727,#727,#725,.T.);
#729=ORIENTED_EDGE('',*,*,#728,.T.);
#730=EDGE_LOOP('',(#729));
#731=FACE_BOUND('',#730,.T.);
#732=CARTESIAN_POINT('',(-16.7944331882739,0.,-4.36913462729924));
#733=DIRECTION('',(0.,1.,0.));
#734=DIRECTION('',(1.,0.,0.));
#735=AXIS2_PLACEMENT_3D('',#732,#733,#734);
#736=CIRCLE('',#735,4.);
#737=CARTESIAN_POINT('',(-12.7944331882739,0.,-4.36913462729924));
#738=VERTEX_POINT('',#737);
#739=EDGE_CURVE('E245',#738,#738,#736,.T.);
#740=ORIENTED_EDGE('',*,*,#739,.T.);
#741=EDGE_LOOP('',(#740));
#742=FACE_BOUND('',#741,.T.);
#743=CARTESIAN_POINT('',(-21.8918719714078,0.,9.29762764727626));
#744=DIRECTION('',(0.,1.,0.));
#745=DIRECTION('',(1.,0.,0.));
#746=AXIS2_PLACEMENT_3D('',#743,#744,#745);
#747=CIRCLE('',#746,4.);
#748=CARTESIAN_POINT('',(-17.8918719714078,0.,9.29762764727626));
#749=VERTEX_POINT('',#748);
#750=EDGE_CURVE('E239',#749,#749,#747,.T.);
#751=ORIENTED_EDGE('',*,*,#750,.T.);
#752=EDGE_LOOP('',(#751));
#753=FACE_BOUND('',#752,.T.);
#754=CARTESIAN_POINT('',(-24.9924431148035,0.,23.5507231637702));
#755=DIRECTION('',(0.,1.,0.));
#756=DIRECTION('',(1.,0.,0.));
#757=AXIS2_PLACEMENT_3D('',#754,#755,#756);
#758=CIRCLE('',#757,4.);
#759=CARTESIAN_POINT('',(-20.9924431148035,0.,23.5507231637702));
#760=VERTEX_POINT('',#759);
#761=EDGE_CURVE('E233',#760,#760,#758,.T.);
#762=ORIENTED_EDGE('',*,*,#761,.T.);
#763=EDGE_LOOP('',(#762));
#764=FACE_BOUND('',#763,.T.);
#765=CARTESIAN_POINT('',(21.4382302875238,0.,-27.1625357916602));
#766=DIRECTION('',(0.,1.,0.));
#767=DIRECTION('',(1.,0.,0.));
#768=AXIS2_PLACEMENT_3D('',#765,#766,#767);
#769=CIRCLE('',#768,4.);
#770=CARTESIAN_POINT('',(25.4382302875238,0.,-27.1625357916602));
#771=VERTEX_POINT('',#770);
#772=EDGE_CURVE('E227',#771,#771,#769,.T.);
#773=ORIENTED_EDGE('',*,*,#772,.T.);
#774=EDGE_LOOP('',(#773));
#775=FACE_BOUND('',#774,.T.);
#776=CARTESIAN_POINT('',(10.9374642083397,0.,-16.6617697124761));
#777=DIRECTION('',(0.,1.,0.));
#778=DIRECTION('',(1.,0.,0.));
#779=AXIS2_PLACEMENT_3D('',#776,#777,#778);
#780=CIRCLE('',#779,4.);
#781=CARTESIAN_POINT('',(14.9374642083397,0.,-16.6617697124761));
#782=VERTEX_POINT('',#781);
#783=EDGE_CURVE('E221',#782,#782,#780,.T.);
#784=ORIENTED_EDGE('',*,*,#783,.T.);
#785=EDGE_LOOP('',(#784));
#786=FACE_BOUND('',#785,.T.);
#787=CARTESIAN_POINT('',(69.075825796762,0.,-29.6819898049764));
#788=DIRECTION('',(0.,1.,0.));
#789=DIRECTION('',(1.,0.,0.));
#790=AXIS2_PLACEMENT_3D('',#787,#788,#789);
#791=CIRCLE('',#790,4.);
#792=CARTESIAN_POINT('',(73.0758257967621,0.,-29.6819898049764));
#793=VERTEX_POINT('',#792);
#794=EDGE_CURVE('E215',#793,#793,#791,.T.);
#795=ORIENTED_EDGE('',*,*,#794,.T.);
#796=EDGE_LOOP('',(#795));
#797=FACE_BOUND('',#796,.T.);
#798=CARTESIAN_POINT('',(2.41966725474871,0.,-4.49709497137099));
#799=DIRECTION('',(0.,1.,0.));
#800=DIRECTION('',(1.,0.,0.));
#801=AXIS2_PLACEMENT_3D('',#798,#799,#800);
#802=CIRCLE('',#801,4.);
#803=CARTESIAN_POINT('',(6.41966725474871,0.,-4.49709497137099));
#804=VERTEX_POINT('',#803);
#805=EDGE_CURVE('E209',#804,#804,#802,.T.);
#806=ORIENTED_EDGE('',*,*,#805,.T.);
#807=EDGE_LOOP('',(#806));
#808=FACE_BOUND('',#807,.T.);
#809=CARTESIAN_POINT('',(55.1388379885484,0.,-26.7195915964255));
#810=DIRECTION('',(0.,1.,0.));
#811=DIRECTION('',(1.,0.,0.));
#812=AXIS2_PLACEMENT_3D('',#809,#810,#811);
#813=CIRCLE('',#812,4.);
#814=CARTESIAN_POINT('',(59.1388379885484,0.,-26.7195915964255));
#815=VERTEX_POINT('',#814);
#816=EDGE_CURVE('E203',#815,#815,#813,.T.);
#817=ORIENTED_EDGE('',*,*,#816,.T.);
#818=EDGE_LOOP('',(#817));
#819=FACE_BOUND('',#818,.T.);
#820=CARTESIAN_POINT('',(-3.85635162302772,0.,8.96187094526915));
#821=DIRECTION('',(0.,1.,0.));
#822=DIRECTION('',(1.,0.,0.));
#823=AXIS2_PLACEMENT_3D('',#820,#821,#822);
#824=CIRCLE('',#823,4.);
#825=CARTESIAN_POINT('',(0.143648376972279,0.,8.96187094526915));
#826=VERTEX_POINT('',#825);
#827=EDGE_CURVE('E197',#826,#826,#824,.T.);
#828=ORIENTED_EDGE('',*,*,#827,.T.);
#829=EDGE_LOOP('',(#828));
#830=FACE_BOUND('',#829,.T.);
#831=CARTESIAN_POINT('',(42.1223240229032,0.,-20.924266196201));
#832=DIRECTION('',(0.,1.,0.));
#833=DIRECTION('',(1.,0.,0.));
#834=AXIS2_PLACEMENT_3D('',#831,#832,#833);
#835=CIRCLE('',#834,4.);
#836=CARTESIAN_POINT('',(46.1223240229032,0.,-20.924266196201));
#837=VERTEX_POINT('',#836);
#838=EDGE_CURVE('E191',#837,#837,#835,.T.);
#839=ORIENTED_EDGE('',*,*,#838,.T.);
#840=EDGE_LOOP('',(#839));
#841=FACE_BOUND('',#840,.T.);
#842=CARTESIAN_POINT('',(-7.699898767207,0.,23.3061841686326));
#843=DIRECTION('',(0.,1.,0.));
#844=DIRECTION('',(1.,0.,0.));
#845=AXIS2_PLACEMENT_3D('',#842,#843,#844);
#846=CIRCLE('',#845,4.);
#847=CARTESIAN_POINT('',(-3.699898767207,0.,23.3061841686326));
#848=VERTEX_POINT('',#847);
#849=EDGE_CURVE('E185',#848,#848,#846,.T.);
#850=ORIENTED_EDGE('',*,*,#849,.T.);
#851=EDGE_LOOP('',(#850));
#852=FACE_BOUND('',#851,.T.);
#853=CARTESIAN_POINT('',(30.5951680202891,0.,-12.5492971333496));
#854=DIRECTION('',(0.,1.,0.));
#855=DIRECTION('',(1.,0.,0.));
#856=AXIS2_PLACEMENT_3D('',#853,#854,#855);
#857=CIRCLE('',#856,4.);
#858=CARTESIAN_POINT('',(34.5951680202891,0.,-12.5492971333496));
#859=VERTEX_POINT('',#858);
#860=EDGE_CURVE('E179',#859,#859,#857,.T.);
#861=ORIENTED_EDGE('',*,*,#860,.T.);
#862=EDGE_LOOP('',(#861));
#863=FACE_BOUND('',#862,.T.);
#864=CARTESIAN_POINT('',(21.0611620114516,0.,-1.96071074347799));
#865=DIRECTION('',(0.,1.,0.));
#866=DIRECTION('',(1.,0.,0.));
#867=AXIS2_PLACEMENT_3D('',#864,#865,#866);
#868=CIRCLE('',#867,4.);
#869=CARTESIAN_POINT('',(25.0611620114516,0.,-1.96071074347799));
#870=VERTEX_POINT('',#869);
#871=EDGE_CURVE('E173',#870,#870,#868,.T.);
#872=ORIENTED_EDGE('',*,*,#871,.T.);
#873=EDGE_LOOP('',(#872));
#874=FACE_BOUND('',#873,.T.);
#875=CARTESIAN_POINT('',(13.9369878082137,0.,10.3787209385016));
#876=DIRECTION('',(0.,1.,0.));
#877=DIRECTION('',(1.,0.,0.));
#878=AXIS2_PLACEMENT_3D('',#875,#876,#877);
#879=CIRCLE('',#878,4.);
#880=CARTESIAN_POINT('',(17.9369878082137,0.,10.3787209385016));
#881=VERTEX_POINT('',#880);
#882=EDGE_CURVE('E167',#881,#881,#879,.T.);
#883=ORIENTED_EDGE('',*,*,#882,.T.);
#884=EDGE_LOOP('',(#883));
#885=FACE_BOUND('',#884,.T.);
#886=CARTESIAN_POINT('',(9.53400600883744,0.,23.9297055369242));
#887=DIRECTION('',(0.,1.,0.));
#888=DIRECTION('',(1.,0.,0.));
#889=AXIS2_PLACEMENT_3D('',#886,#887,#888);
#890=CIRCLE('',#889,4.);
#891=CARTESIAN_POINT('',(13.5340060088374,0.,23.9297055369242));
#892=VERTEX_POINT('',#891);
#893=EDGE_CURVE('E161',#892,#892,#890,.T.);
#894=ORIENTED_EDGE('',*,*,#893,.T.);
#895=EDGE_LOOP('',(#894));
#896=FACE_BOUND('',#895,.T.);
#897=CARTESIAN_POINT('',(68.9253615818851,0.,-12.4962215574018));
#898=DIRECTION('',(0.,1.,0.));
#899=DIRECTION('',(1.,0.,0.));
#900=AXIS2_PLACEMENT_3D('',#897,#898,#899);
#901=CIRCLE('',#900,4.);
#902=CARTESIAN_POINT('',(72.9253615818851,0.,-12.4962215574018));
#903=VERTEX_POINT('',#902);
#904=EDGE_CURVE('E155',#903,#903,#901,.T.);
#905=ORIENTED_EDGE('',*,*,#904,.T.);
#906=EDGE_LOOP('',(#905));
#907=FACE_BOUND('',#906,.T.);
#908=CARTESIAN_POINT('',(54.9654326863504,0.,-8.39721659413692));
#909=DIRECTION('',(0.,1.,0.));
#910=DIRECTION('',(1.,0.,0.));
#911=AXIS2_PLACEMENT_3D('',#908,#909,#910);
#912=CIRCLE('',#911,4.);
#913=CARTESIAN_POINT('',(58.9654326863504,0.,-8.39721659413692));
#914=VERTEX_POINT('',#913);
#915=EDGE_CURVE('E149',#914,#914,#912,.T.);
#916=ORIENTED_EDGE('',*,*,#915,.T.);
#917=EDGE_LOOP('',(#916));
#918=FACE_BOUND('',#917,.T.);
#919=CARTESIAN_POINT('',(42.7258021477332,0.,-0.531283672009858));
#920=DIRECTION('',(0.,1.,0.));
#921=DIRECTION('',(1.,0.,0.));
#922=AXIS2_PLACEMENT_3D('',#919,#920,#921);
#923=CIRCLE('',#922,4.);
#924=CARTESIAN_POINT('',(46.7258021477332,0.,-0.531283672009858));
#925=VERTEX_POINT('',#924);
#926=EDGE_CURVE('E143',#925,#925,#923,.T.);
#927=ORIENTED_EDGE('',*,*,#926,.T.);
#928=EDGE_LOOP('',(#927));
#929=FACE_BOUND('',#928,.T.);
#930=CARTESIAN_POINT('',(33.1980520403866,0.,10.4643261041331));
#931=DIRECTION('',(0.,1.,0.));
#932=DIRECTION('',(1.,0.,0.));
#933=AXIS2_PLACEMENT_3D('',#930,#931,#932);
#934=CIRCLE('',#933,4.);
#935=CARTESIAN_POINT('',(37.1980520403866,0.,10.4643261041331));
#936=VERTEX_POINT('',#935);
#937=EDGE_CURVE('E137',#936,#936,#934,.T.);
#938=ORIENTED_EDGE('',*,*,#937,.T.);
#939=EDGE_LOOP('',(#938));
#940=FACE_BOUND('',#939,.T.);
#941=CARTESIAN_POINT('',(27.1540640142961,0.,23.6988138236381));
#942=DIRECTION('',(0.,1.,0.));
#943=DIRECTION('',(1.,0.,0.));
#944=AXIS2_PLACEMENT_3D('',#941,#942,#943);
#945=CIRCLE('',#944,4.);
#946=CARTESIAN_POINT('',(31.1540640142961,0.,23.6988138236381));
#947=VERTEX_POINT('',#946);
#948=EDGE_CURVE('E131',#947,#947,#945,.T.);
#949=ORIENTED_EDGE('',*,*,#948,.T.);
#950=EDGE_LOOP('',(#949));
#951=FACE_BOUND('',#950,.T.);
#952=CARTESIAN_POINT('',(68.6170037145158,0.,4.87672250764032));
#953=DIRECTION('',(0.,1.,0.));
#954=DIRECTION('',(1.,0.,0.));
#955=AXIS2_PLACEMENT_3D('',#952,#953,#954);
#956=CIRCLE('',#955,4.);
#957=CARTESIAN_POINT('',(72.6170037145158,0.,4.87672250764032));
#958=VERTEX_POINT('',#957);
#959=EDGE_CURVE('E125',#958,#958,#956,.T.);
#960=ORIENTED_EDGE('',*,*,#959,.T.);
#961=EDGE_LOOP('',(#960));
#962=FACE_BOUND('',#961,.T.);
#963=CARTESIAN_POINT('',(54.9529165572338,0.,11.4570000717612));
#964=DIRECTION('',(0.,1.,0.));
#965=DIRECTION('',(1.,0.,0.));
#966=AXIS2_PLACEMENT_3D('',#963,#964,#965);
#967=CIRCLE('',#966,4.);
#968=CARTESIAN_POINT('',(58.9529165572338,0.,11.4570000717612));
#969=VERTEX_POINT('',#968);
#970=EDGE_CURVE('E119',#969,#969,#967,.T.);
#971=ORIENTED_EDGE('',*,*,#970,.T.);
#972=EDGE_LOOP('',(#971));
#973=FACE_BOUND('',#972,.T.);
#974=CARTESIAN_POINT('',(45.4970748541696,0.,23.3142505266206));
#975=DIRECTION('',(0.,1.,0.));
#976=DIRECTION('',(1.,0.,0.));
#977=AXIS2_PLACEMENT_3D('',#974,#975,#976);
#978=CIRCLE('',#977,4.);
#979=CARTESIAN_POINT('',(49.4970748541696,0.,23.3142505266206));
#980=VERTEX_POINT('',#979);
#981=EDGE_CURVE('E113',#980,#980,#978,.T.);
#982=ORIENTED_EDGE('',*,*,#981,.T.);
#983=EDGE_LOOP('',(#982));
#984=FACE_BOUND('',#983,.T.);
#985=CARTESIAN_POINT('',(64.1517221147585,0.,26.0517221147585));
#986=DIRECTION('',(0.,1.,0.));
#987=DIRECTION('',(1.,0.,0.));
#988=AXIS2_PLACEMENT_3D('',#985,#986,#987);
#989=CIRCLE('',#988,4.);
#990=CARTESIAN_POINT('',(68.1517221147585,0.,26.0517221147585));
#991=VERTEX_POINT('',#990);
#992=EDGE_CURVE('E99',#991,#991,#989,.T.);
#993=ORIENTED_EDGE('',*,*,#992,.T.);
#994=EDGE_LOOP('',(#993));
#995=FACE_BOUND('',#994,.T.);
#996=ORIENTED_EDGE('',*,*,#32,.F.);
#997=ORIENTED_EDGE('',*,*,#130,.F.);
#998=ORIENTED_EDGE('',*,*,#101,.F.);
#999=ORIENTED_EDGE('',*,*,#70,.F.);
#1000=EDGE_LOOP('',(#996,#997,#998,#999));
#1001=FACE_BOUND('',#1000,.T.);
#1002=ADVANCED_FACE('F107',(#588,#599,#610,#621,#632,#643,#654,#665,#676,#687,#698,#709,#720,
#731,#742,#753,#764,#775,#786,#797,#808,#819,#830,#841,#852,#863,#874,#885,#896,#907,#918,#929,
#940,#951,#962,#973,#984,#995,#1001),#577,.F.);
#1003=CARTESIAN_POINT('',(64.1517221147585,0.,26.0517221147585));
#1004=DIRECTION('',(0.,1.,0.));
#1005=DIRECTION('',(0.,0.,1.));
#1006=AXIS2_PLACEMENT_3D('',#1003,#1004,#1005);
#1007=CYLINDRICAL_SURFACE('',#1006,4.);
#1008=ORIENTED_EDGE('',*,*,#992,.F.);
#1009=EDGE_LOOP('',(#1008));
#1010=FACE_BOUND('',#1009,.T.);
#1011=ORIENTED_EDGE('',*,*,#562,.T.);
#1012=EDGE_LOOP('',(#1011));
#1013=FACE_BOUND('',#1012,.T.);
#1014=ADVANCED_FACE('F424',(#1010,#1013),#1007,.F.);
#1015=CARTESIAN_POINT('',(45.4970748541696,0.,23.3142505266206));
#1016=DIRECTION('',(0.,1.,0.));
#1017=DIRECTION('',(0.,0.,1.));
#1018=AXIS2_PLACEMENT_3D('',#1015,#1016,#1017);
#1019=CYLINDRICAL_SURFACE('',#1018,4.);
#1020=ORIENTED_EDGE('',*,*,#981,.F.);
#1021=EDGE_LOOP('',(#1020));
#1022=FACE_BOUND('',#1021,.T.);
#1023=ORIENTED_EDGE('',*,*,#551,.T.);
#1024=EDGE_LOOP('',(#1023));
#1025=FACE_BOUND('',#1024,.T.);
#1026=ADVANCED_FACE('F426',(#1022,#1025),#1019,.F.);
#1027=CARTESIAN_POINT('',(54.9529165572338,0.,11.4570000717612));
#1028=DIRECTION('',(0.,1.,0.));
#1029=DIRECTION('',(0.,0.,1.));
#1030=AXIS2_PLACEMENT_3D('',#1027,#1028,#1029);
#1031=CYLINDRICAL_SURFACE('',#1030,4.);
#1032=ORIENTED_EDGE('',*,*,#970,.F.);
#1033=EDGE_LOOP('',(#1032));
#1034=FACE_BOUND('',#1033,.T.);
#1035=ORIENTED_EDGE('',*,*,#540,.T.);
#1036=EDGE_LOOP('',(#1035));
#1037=FACE_BOUND('',#1036,.T.);
#1038=ADVANCED_FACE('F433',(#1034,#1037),#1031,.F.);
#1039=CARTESIAN_POINT('',(68.6170037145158,0.,4.87672250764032));
#1040=DIRECTION('',(0.,1.,0.));
#1041=DIRECTION('',(0.,0.,1.));
#1042=AXIS2_PLACEMENT_3D('',#1039,#1040,#1041);
#1043=CYLINDRICAL_SURFACE('',#1042,4.);
#1044=ORIENTED_EDGE('',*,*,#959,.F.);
#1045=EDGE_LOOP('',(#1044));
#1046=FACE_BOUND('',#1045,.T.);
#1047=ORIENTED_EDGE('',*,*,#529,.T.);
#1048=EDGE_LOOP('',(#1047));
#1049=FACE_BOUND('',#1048,.T.);
#1050=ADVANCED_FACE('F479',(#1046,#1049),#1043,.F.);
#1051=CARTESIAN_POINT('',(27.1540640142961,0.,23.6988138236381));
#1052=DIRECTION('',(0.,1.,0.));
#1053=DIRECTION('',(0.,0.,1.));
#1054=AXIS2_PLACEMENT_3D('',#1051,#1052,#1053);
#1055=CYLINDRICAL_SURFACE('',#1054,4.);
#1056=ORIENTED_EDGE('',*,*,#948,.F.);
#1057=EDGE_LOOP('',(#1056));
#1058=FACE_BOUND('',#1057,.T.);
#1059=ORIENTED_EDGE('',*,*,#518,.T.);
#1060=EDGE_LOOP('',(#1059));
#1061=FACE_BOUND('',#1060,.T.);
#1062=ADVANCED_FACE('F489',(#1058,#1061),#1055,.F.);
#1063=CARTESIAN_POINT('',(33.1980520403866,0.,10.4643261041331));
#1064=DIRECTION('',(0.,1.,0.));
#1065=DIRECTION('',(0.,0.,1.));
#1066=AXIS2_PLACEMENT_3D('',#1063,#1064,#1065);
#1067=CYLINDRICAL_SURFACE('',#1066,4.);
#1068=ORIENTED_EDGE('',*,*,#937,.F.);
#1069=EDGE_LOOP('',(#1068));
#1070=FACE_BOUND('',#1069,.T.);
#1071=ORIENTED_EDGE('',*,*,#507,.T.);
#1072=EDGE_LOOP('',(#1071));
#1073=FACE_BOUND('',#1072,.T.);
#1074=ADVANCED_FACE('F499',(#1070,#1073),#1067,.F.);
#1075=CARTESIAN_POINT('',(42.7258021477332,0.,-0.531283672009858));
#1076=DIRECTION('',(0.,1.,0.));
#1077=DIRECTION('',(0.,0.,1.));
#1078=AXIS2_PLACEMENT_3D('',#1075,#1076,#1077);
#1079=CYLINDRICAL_SURFACE('',#1078,4.);
#1080=ORIENTED_EDGE('',*,*,#926,.F.);
#1081=EDGE_LOOP('',(#1080));
#1082=FACE_BOUND('',#1081,.T.);
#1083=ORIENTED_EDGE('',*,*,#496,.T.);
#1084=EDGE_LOOP('',(#1083));
#1085=FACE_BOUND('',#1084,.T.);
#1086=ADVANCED_FACE('F509',(#1082,#1085),#1079,.F.);
#1087=CARTESIAN_POINT('',(54.9654326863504,0.,-8.39721659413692));
#1088=DIRECTION('',(0.,1.,0.));
#1089=DIRECTION('',(0.,0.,1.));
#1090=AXIS2_PLACEMENT_3D('',#1087,#1088,#1089);
#1091=CYLINDRICAL_SURFACE('',#1090,4.);
#1092=ORIENTED_EDGE('',*,*,#915,.F.);
#1093=EDGE_LOOP('',(#1092));
#1094=FACE_BOUND('',#1093,.T.);
#1095=ORIENTED_EDGE('',*,*,#485,.T.);
#1096=EDGE_LOOP('',(#1095));
#1097=FACE_BOUND('',#1096,.T.);
#1098=ADVANCED_FACE('F519',(#1094,#1097),#1091,.F.);
#1099=CARTESIAN_POINT('',(68.9253615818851,0.,-12.4962215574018));
#1100=DIRECTION('',(0.,1.,0.));
#1101=DIRECTION('',(0.,0.,1.));
#1102=AXIS2_PLACEMENT_3D('',#1099,#1100,#1101);
#1103=CYLINDRICAL_SURFACE('',#1102,4.);
#1104=ORIENTED_EDGE('',*,*,#904,.F.);
#1105=EDGE_LOOP('',(#1104));
#1106=FACE_BOUND('',#1105,.T.);
#1107=ORIENTED_EDGE('',*,*,#474,.T.);
#1108=EDGE_LOOP('',(#1107));
#1109=FACE_BOUND('',#1108,.T.);
#1110=ADVANCED_FACE('F529',(#1106,#1109),#1103,.F.);
#1111=CARTESIAN_POINT('',(9.53400600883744,0.,23.9297055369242));
#1112=DIRECTION('',(0.,1.,0.));
#1113=DIRECTION('',(0.,0.,1.));
#1114=AXIS2_PLACEMENT_3D('',#1111,#1112,#1113);
#1115=CYLINDRICAL_SURFACE('',#1114,4.);
#1116=ORIENTED_EDGE('',*,*,#893,.F.);
#1117=EDGE_LOOP('',(#1116));
#1118=FACE_BOUND('',#1117,.T.);
#1119=ORIENTED_EDGE('',*,*,#463,.T.);
#1120=EDGE_LOOP('',(#1119));
#1121=FACE_BOUND('',#1120,.T.);
#1122=ADVANCED_FACE('F539',(#1118,#1121),#1115,.F.);
#1123=CARTESIAN_POINT('',(13.9369878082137,0.,10.3787209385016));
#1124=DIRECTION('',(0.,1.,0.));
#1125=DIRECTION('',(0.,0.,1.));
#1126=AXIS2_PLACEMENT_3D('',#1123,#1124,#1125);
#1127=CYLINDRICAL_SURFACE('',#1126,4.);
#1128=ORIENTED_EDGE('',*,*,#882,.F.);
#1129=EDGE_LOOP('',(#1128));
#1130=FACE_BOUND('',#1129,.T.);
#1131=ORIENTED_EDGE('',*,*,#452,.T.);
#1132=EDGE_LOOP('',(#1131));
#1133=FACE_BOUND('',#1132,.T.);
#1134=ADVANCED_FACE('F549',(#1130,#1133),#1127,.F.);
#1135=CARTESIAN_POINT('',(21.0611620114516,0.,-1.96071074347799));
#1136=DIRECTION('',(0.,1.,0.));
#1137=DIRECTION('',(0.,0.,1.));
#1138=AXIS2_PLACEMENT_3D('',#1135,#1136,#1137);
#1139=CYLINDRICAL_SURFACE('',#1138,4.);
#1140=ORIENTED_EDGE('',*,*,#871,.F.);
#1141=EDGE_LOOP('',(#1140));
#1142=FACE_BOUND('',#1141,.T.);
#1143=ORIENTED_EDGE('',*,*,#441,.T.);
#1144=EDGE_LOOP('',(#1143));
#1145=FACE_BOUND('',#1144,.T.);
#1146=ADVANCED_FACE('F559',(#1142,#1145),#1139,.F.);
#1147=CARTESIAN_POINT('',(30.5951680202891,0.,-12.5492971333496));
#1148=DIRECTION('',(0.,1.,0.));
#1149=DIRECTION('',(0.,0.,1.));
#1150=AXIS2_PLACEMENT_3D('',#1147,#1148,#1149);
#1151=CYLINDRICAL_SURFACE('',#1150,4.);
#1152=ORIENTED_EDGE('',*,*,#860,.F.);
#1153=EDGE_LOOP('',(#1152));
#1154=FACE_BOUND('',#1153,.T.);
#1155=ORIENTED_EDGE('',*,*,#430,.T.);
#1156=EDGE_LOOP('',(#1155));
#1157=FACE_BOUND('',#1156,.T.);
#1158=ADVANCED_FACE('F569',(#1154,#1157),#1151,.F.);
#1159=CARTESIAN_POINT('',(-7.699898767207,0.,23.3061841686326));
#1160=DIRECTION('',(0.,1.,0.));
#1161=DIRECTION('',(0.,0.,1.));
#1162=AXIS2_PLACEMENT_3D('',#1159,#1160,#1161);
#1163=CYLINDRICAL_SURFACE('',#1162,4.);
#1164=ORIENTED_EDGE('',*,*,#849,.F.);
#1165=EDGE_LOOP('',(#1164));
#1166=FACE_BOUND('',#1165,.T.);
#1167=ORIENTED_EDGE('',*,*,#419,.T.);
#1168=EDGE_LOOP('',(#1167));
#1169=FACE_BOUND('',#1168,.T.);
#1170=ADVANCED_FACE('F579',(#1166,#1169),#1163,.F.);
#1171=CARTESIAN_POINT('',(42.1223240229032,0.,-20.924266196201));
#1172=DIRECTION('',(0.,1.,0.));
#1173=DIRECTION('',(0.,0.,1.));
#1174=AXIS2_PLACEMENT_3D('',#1171,#1172,#1173);
#1175=CYLINDRICAL_SURFACE('',#1174,4.);
#1176=ORIENTED_EDGE('',*,*,#838,.F.);
#1177=EDGE_LOOP('',(#1176));
#1178=FACE_BOUND('',#1177,.T.);
#1179=ORIENTED_EDGE('',*,*,#408,.T.);
#1180=EDGE_LOOP('',(#1179));
#1181=FACE_BOUND('',#1180,.T.);
#1182=ADVANCED_FACE('F589',(#1178,#1181),#1175,.F.);
#1183=CARTESIAN_POINT('',(-3.85635162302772,0.,8.96187094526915));
#1184=DIRECTION('',(0.,1.,0.));
#1185=DIRECTION('',(0.,0.,1.));
#1186=AXIS2_PLACEMENT_3D('',#1183,#1184,#1185);
#1187=CYLINDRICAL_SURFACE('',#1186,4.);
#1188=ORIENTED_EDGE('',*,*,#827,.F.);
#1189=EDGE_LOOP('',(#1188));
#1190=FACE_BOUND('',#1189,.T.);
#1191=ORIENTED_EDGE('',*,*,#397,.T.);
#1192=EDGE_LOOP('',(#1191));
#1193=FACE_BOUND('',#1192,.T.);
#1194=ADVANCED_FACE('F599',(#1190,#1193),#1187,.F.);
#1195=CARTESIAN_POINT('',(55.1388379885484,0.,-26.7195915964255));
#1196=DIRECTION('',(0.,1.,0.));
#1197=DIRECTION('',(0.,0.,1.));
#1198=AXIS2_PLACEMENT_3D('',#1195,#1196,#1197);
#1199=CYLINDRICAL_SURFACE('',#1198,4.);
#1200=ORIENTED_EDGE('',*,*,#816,.F.);
#1201=EDGE_LOOP('',(#1200));
#1202=FACE_BOUND('',#1201,.T.);
#1203=ORIENTED_EDGE('',*,*,#386,.T.);
#1204=EDGE_LOOP('',(#1203));
#1205=FACE_BOUND('',#1204,.T.);
#1206=ADVANCED_FACE('F609',(#1202,#1205),#1199,.F.);
#1207=CARTESIAN_POINT('',(2.41966725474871,0.,-4.49709497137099));
#1208=DIRECTION('',(0.,1.,0.));
#1209=DIRECTION('',(0.,0.,1.));
#1210=AXIS2_PLACEMENT_3D('',#1207,#1208,#1209);
#1211=CYLINDRICAL_SURFACE('',#1210,4.);
#1212=ORIENTED_EDGE('',*,*,#805,.F.);
#1213=EDGE_LOOP('',(#1212));
#1214=FACE_BOUND('',#1213,.T.);
#1215=ORIENTED_EDGE('',*,*,#375,.T.);
#1216=EDGE_LOOP('',(#1215));
#1217=FACE_BOUND('',#1216,.T.);
#1218=ADVANCED_FACE('F619',(#1214,#1217),#1211,.F.);
#1219=CARTESIAN_POINT('',(69.075825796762,0.,-29.6819898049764));
#1220=DIRECTION('',(0.,1.,0.));
#1221=DIRECTION('',(0.,0.,1.));
#1222=AXIS2_PLACEMENT_3D('',#1219,#1220,#1221);
#1223=CYLINDRICAL_SURFACE('',#1222,4.);
#1224=ORIENTED_EDGE('',*,*,#794,.F.);
#1225=EDGE_LOOP('',(#1224));
#1226=FACE_BOUND('',#1225,.T.);
#1227=ORIENTED_EDGE('',*,*,#364,.T.);
#1228=EDGE_LOOP('',(#1227));
#1229=FACE_BOUND('',#1228,.T.);
#1230=ADVANCED_FACE('F629',(#1226,#1229),#1223,.F.);
#1231=CARTESIAN_POINT('',(10.9374642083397,0.,-16.6617697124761));
#1232=DIRECTION('',(0.,1.,0.));
#1233=DIRECTION('',(0.,0.,1.));
#1234=AXIS2_PLACEMENT_3D('',#1231,#1232,#1233);
#1235=CYLINDRICAL_SURFACE('',#1234,4.);
#1236=ORIENTED_EDGE('',*,*,#783,.F.);
#1237=EDGE_LOOP('',(#1236));
#1238=FACE_BOUND('',#1237,.T.);
#1239=ORIENTED_EDGE('',*,*,#353,.T.);
#1240=EDGE_LOOP('',(#1239));
#1241=FACE_BOUND('',#1240,.T.);
#1242=ADVANCED_FACE('F639',(#1238,#1241),#1235,.F.);
#1243=CARTESIAN_POINT('',(21.4382302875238,0.,-27.1625357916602));
#1244=DIRECTION('',(0.,1.,0.));
#1245=DIRECTION('',(0.,0.,1.));
#1246=AXIS2_PLACEMENT_3D('',#1243,#1244,#1245);
#1247=CYLINDRICAL_SURFACE('',#1246,4.);
#1248=ORIENTED_EDGE('',*,*,#772,.F.);
#1249=EDGE_LOOP('',(#1248));
#1250=FACE_BOUND('',#1249,.T.);
#1251=ORIENTED_EDGE('',*,*,#342,.T.);
#1252=EDGE_LOOP('',(#1251));
#1253=FACE_BOUND('',#1252,.T.);
#1254=ADVANCED_FACE('F649',(#1250,#1253),#1247,.F.);
#1255=CARTESIAN_POINT('',(-24.9924431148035,0.,23.5507231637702));
#1256=DIRECTION('',(0.,1.,0.));
#1257=DIRECTION('',(0.,0.,1.));
#1258=AXIS2_PLACEMENT_3D('',#1255,#1256,#1257);
#1259=CYLINDRICAL_SURFACE('',#1258,4.);
#1260=ORIENTED_EDGE('',*,*,#761,.F.);
#1261=EDGE_LOOP('',(#1260));
#1262=FACE_BOUND('',#1261,.T.);
#1263=ORIENTED_EDGE('',*,*,#331,.T.);
#1264=EDGE_LOOP('',(#1263));
#1265=FACE_BOUND('',#1264,.T.);
#1266=ADVANCED_FACE('F659',(#1262,#1265),#1259,.F.);
#1267=CARTESIAN_POINT('',(-21.8918719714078,0.,9.29762764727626));
#1268=DIRECTION('',(0.,1.,0.));
#1269=DIRECTION('',(0.,0.,1.));
#1270=AXIS2_PLACEMENT_3D('',#1267,#1268,#1269);
#1271=CYLINDRICAL_SURFACE('',#1270,4.);
#1272=ORIENTED_EDGE('',*,*,#750,.F.);
#1273=EDGE_LOOP('',(#1272));
#1274=FACE_BOUND('',#1273,.T.);
#1275=ORIENTED_EDGE('',*,*,#320,.T.);
#1276=EDGE_LOOP('',(#1275));
#1277=FACE_BOUND('',#1276,.T.);
#1278=ADVANCED_FACE('F669',(#1274,#1277),#1271,.F.);
#1279=CARTESIAN_POINT('',(-16.7944331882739,0.,-4.36913462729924));
#1280=DIRECTION('',(0.,1.,0.));
#1281=DIRECTION('',(0.,0.,1.));
#1282=AXIS2_PLACEMENT_3D('',#1279,#1280,#1281);
#1283=CYLINDRICAL_SURFACE('',#1282,4.);
#1284=ORIENTED_EDGE('',*,*,#739,.F.);
#1285=EDGE_LOOP('',(#1284));
#1286=FACE_BOUND('',#1285,.T.);
#1287=ORIENTED_EDGE('',*,*,#309,.T.);
#1288=EDGE_LOOP('',(#1287));
#1289=FACE_BOUND('',#1288,.T.);
#1290=ADVANCED_FACE('F679',(#1286,#1289),#1283,.F.);
#1291=CARTESIAN_POINT('',(-9.80389591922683,0.,-17.1713477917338));
#1292=DIRECTION('',(0.,1.,0.));
#1293=DIRECTION('',(0.,0.,1.));
#1294=AXIS2_PLACEMENT_3D('',#1291,#1292,#1293);
#1295=CYLINDRICAL_SURFACE('',#1294,4.);
#1296=ORIENTED_EDGE('',*,*,#728,.F.);
#1297=EDGE_LOOP('',(#1296));
#1298=FACE_BOUND('',#1297,.T.);
#1299=ORIENTED_EDGE('',*,*,#298,.T.);
#1300=EDGE_LOOP('',(#1299));
#1301=FACE_BOUND('',#1300,.T.);
#1302=ADVANCED_FACE('F689',(#1298,#1301),#1295,.F.);
#1303=CARTESIAN_POINT('',(-42.1313716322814,0.,23.1512713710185));
#1304=DIRECTION('',(0.,1.,0.));
#1305=DIRECTION('',(0.,0.,1.));
#1306=AXIS2_PLACEMENT_3D('',#1303,#1304,#1305);
#1307=CYLINDRICAL_SURFACE('',#1306,4.);
#1308=ORIENTED_EDGE('',*,*,#717,.F.);
#1309=EDGE_LOOP('',(#1308));
#1310=FACE_BOUND('',#1309,.T.);
#1311=ORIENTED_EDGE('',*,*,#287,.T.);
#1312=EDGE_LOOP('',(#1311));
#1313=FACE_BOUND('',#1312,.T.);
#1314=ADVANCED_FACE('F699',(#1310,#1313),#1307,.F.);
#1315=CARTESIAN_POINT('',(-1.06256734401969,0.,-28.8483957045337));
#1316=DIRECTION('',(0.,1.,0.));
#1317=DIRECTION('',(0.,0.,1.));
#1318=AXIS2_PLACEMENT_3D('',#1315,#1316,#1317);
#1319=CYLINDRICAL_SURFACE('',#1318,4.);
#1320=ORIENTED_EDGE('',*,*,#706,.F.);
#1321=EDGE_LOOP('',(#1320));
#1322=FACE_BOUND('',#1321,.T.);
#1323=ORIENTED_EDGE('',*,*,#276,.T.);
#1324=EDGE_LOOP('',(#1323));
#1325=FACE_BOUND('',#1324,.T.);
#1326=ADVANCED_FACE('F709',(#1322,#1325),#1319,.F.);
#1327=CARTESIAN_POINT('',(-39.3247209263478,0.,8.4382931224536));
#1328=DIRECTION('',(0.,1.,0.));
#1329=DIRECTION('',(0.,0.,1.));
#1330=AXIS2_PLACEMENT_3D('',#1327,#1328,#1329);
#1331=CYLINDRICAL_SURFACE('',#1330,4.);
#1332=ORIENTED_EDGE('',*,*,#695,.F.);
#1333=EDGE_LOOP('',(#1332));
#1334=FACE_BOUND('',#1333,.T.);
#1335=ORIENTED_EDGE('',*,*,#265,.T.);
#1336=EDGE_LOOP('',(#1335));
#1337=FACE_BOUND('',#1336,.T.);
#1338=ADVANCED_FACE('F719',(#1334,#1337),#1331,.F.);
#1339=CARTESIAN_POINT('',(-34.6961763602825,0.,-5.80690228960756));
#1340=DIRECTION('',(0.,1.,0.));
#1341=DIRECTION('',(0.,0.,1.));
#1342=AXIS2_PLACEMENT_3D('',#1339,#1340,#1341);
#1343=CYLINDRICAL_SURFACE('',#1342,4.);
#1344=ORIENTED_EDGE('',*,*,#684,.F.);
#1345=EDGE_LOOP('',(#1344));
#1346=FACE_BOUND('',#1345,.T.);
#1347=ORIENTED_EDGE('',*,*,#254,.T.);
#1348=EDGE_LOOP('',(#1347));
#1349=FACE_BOUND('',#1348,.T.);
#1350=ADVANCED_FACE('F729',(#1346,#1349),#1343,.F.);
#1351=CARTESIAN_POINT('',(-28.3187328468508,0.,-19.3596596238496));
#1352=DIRECTION('',(0.,1.,0.));
#1353=DIRECTION('',(0.,0.,1.));
#1354=AXIS2_PLACEMENT_3D('',#1351,#1352,#1353);
#1355=CYLINDRICAL_SURFACE('',#1354,4.);
#1356=ORIENTED_EDGE('',*,*,#673,.F.);
#1357=EDGE_LOOP('',(#1356));
#1358=FACE_BOUND('',#1357,.T.);
#1359=ORIENTED_EDGE('',*,*,#243,.T.);
#1360=EDGE_LOOP('',(#1359));
#1361=FACE_BOUND('',#1360,.T.);
#1362=ADVANCED_FACE('F739',(#1358,#1361),#1355,.F.);
#1363=CARTESIAN_POINT('',(-20.2929664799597,0.,-32.0062438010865));
#1364=DIRECTION('',(0.,1.,0.));
#1365=DIRECTION('',(0.,0.,1.));
#1366=AXIS2_PLACEMENT_3D('',#1363,#1364,#1365);
#1367=CYLINDRICAL_SURFACE('',#1366,4.);
#1368=ORIENTED_EDGE('',*,*,#662,.F.);
#1369=EDGE_LOOP('',(#1368));
#1370=FACE_BOUND('',#1369,.T.);
#1371=ORIENTED_EDGE('',*,*,#232,.T.);
#1372=EDGE_LOOP('',(#1371));
#1373=FACE_BOUND('',#1372,.T.);
#1374=ADVANCED_FACE('F749',(#1370,#1373),#1367,.F.);
#1375=CARTESIAN_POINT('',(-59.3116447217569,0.,23.3622204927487));
#1376=DIRECTION('',(0.,1.,0.));
#1377=DIRECTION('',(0.,0.,1.));
#1378=AXIS2_PLACEMENT_3D('',#1375,#1376,#1377);
#1379=CYLINDRICAL_SURFACE('',#1378,4.);
#1380=ORIENTED_EDGE('',*,*,#651,.F.);
#1381=EDGE_LOOP('',(#1380));
#1382=FACE_BOUND('',#1381,.T.);
#1383=ORIENTED_EDGE('',*,*,#221,.T.);
#1384=EDGE_LOOP('',(#1383));
#1385=FACE_BOUND('',#1384,.T.);
#1386=ADVANCED_FACE('F759',(#1382,#1385),#1379,.F.);
#1387=CARTESIAN_POINT('',(-56.9238354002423,0.,8.79722797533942));
#1388=DIRECTION('',(0.,1.,0.));
#1389=DIRECTION('',(0.,0.,1.));
#1390=AXIS2_PLACEMENT_3D('',#1387,#1388,#1389);
#1391=CYLINDRICAL_SURFACE('',#1390,4.);
#1392=ORIENTED_EDGE('',*,*,#640,.F.);
#1393=EDGE_LOOP('',(#1392));
#1394=FACE_BOUND('',#1393,.T.);
#1395=ORIENTED_EDGE('',*,*,#210,.T.);
#1396=EDGE_LOOP('',(#1395));
#1397=FACE_BOUND('',#1396,.T.);
#1398=ADVANCED_FACE('F769',(#1394,#1397),#1391,.F.);
#1399=CARTESIAN_POINT('',(-52.9752708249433,0.,-5.42421633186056));
#1400=DIRECTION('',(0.,1.,0.));
#1401=DIRECTION('',(0.,0.,1.));
#1402=AXIS2_PLACEMENT_3D('',#1399,#1400,#1401);
#1403=CYLINDRICAL_SURFACE('',#1402,4.);
#1404=ORIENTED_EDGE('',*,*,#629,.F.);
#1405=EDGE_LOOP('',(#1404));
#1406=FACE_BOUND('',#1405,.T.);
#1407=ORIENTED_EDGE('',*,*,#199,.T.);
#1408=EDGE_LOOP('',(#1407));
#1409=FACE_BOUND('',#1408,.T.);
#1410=ADVANCED_FACE('F779',(#1406,#1409),#1403,.F.);
#1411=CARTESIAN_POINT('',(-47.5122443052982,0.,-19.13537899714));
#1412=DIRECTION('',(0.,1.,0.));
#1413=DIRECTION('',(0.,0.,1.));
#1414=AXIS2_PLACEMENT_3D('',#1411,#1412,#1413);
#1415=CYLINDRICAL_SURFACE('',#1414,4.);
#1416=ORIENTED_EDGE('',*,*,#618,.F.);
#1417=EDGE_LOOP('',(#1416));
#1418=FACE_BOUND('',#1417,.T.);
#1419=ORIENTED_EDGE('',*,*,#188,.T.);
#1420=EDGE_LOOP('',(#1419));
#1421=FACE_BOUND('',#1420,.T.);
#1422=ADVANCED_FACE('F789',(#1418,#1421),#1415,.F.);
#1423=CARTESIAN_POINT('',(-40.5988048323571,0.,-32.175509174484));
#1424=DIRECTION('',(0.,1.,0.));
#1425=DIRECTION('',(0.,0.,1.));
#1426=AXIS2_PLACEMENT_3D('',#1423,#1424,#1425);
#1427=CYLINDRICAL_SURFACE('',#1426,4.);
#1428=ORIENTED_EDGE('',*,*,#607,.F.);
#1429=EDGE_LOOP('',(#1428));
#1430=FACE_BOUND('',#1429,.T.);
#1431=ORIENTED_EDGE('',*,*,#177,.T.);
#1432=EDGE_LOOP('',(#1431));
#1433=FACE_BOUND('',#1432,.T.);
#1434=ADVANCED_FACE('F799',(#1430,#1433),#1427,.F.);
#1435=CARTESIAN_POINT('',(-70.546362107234,0.,-6.41502227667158));
#1436=DIRECTION('',(0.,1.,0.));
#1437=DIRECTION('',(0.,0.,1.));
#1438=AXIS2_PLACEMENT_3D('',#1435,#1436,#1437);
#1439=CYLINDRICAL_SURFACE('',#1438,4.);
#1440=ORIENTED_EDGE('',*,*,#596,.F.);
#1441=EDGE_LOOP('',(#1440));
#1442=FACE_BOUND('',#1441,.T.);
#1443=ORIENTED_EDGE('',*,*,#166,.T.);
#1444=EDGE_LOOP('',(#1443));
#1445=FACE_BOUND('',#1444,.T.);
#1446=ADVANCED_FACE('F343',(#1442,#1445),#1439,.F.);
#1447=CARTESIAN_POINT('',(-65.4765030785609,0.,-20.5843290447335));
#1448=DIRECTION('',(0.,1.,0.));
#1449=DIRECTION('',(0.,0.,1.));
#1450=AXIS2_PLACEMENT_3D('',#1447,#1448,#1449);
#1451=CYLINDRICAL_SURFACE('',#1450,4.);
#1452=ORIENTED_EDGE('',*,*,#585,.F.);
#1453=EDGE_LOOP('',(#1452));
#1454=FACE_BOUND('',#1453,.T.);
#1455=ORIENTED_EDGE('',*,*,#155,.T.);
#1456=EDGE_LOOP('',(#1455));
#1457=FACE_BOUND('',#1456,.T.);
#1458=ADVANCED_FACE('F340',(#1454,#1457),#1451,.F.);
#1459=CLOSED_SHELL('',(#58,#89,#120,#142,#572,#1002,#1014,#1026,#1038,#1050,#1062,#1074,#1086,
#1098,#1110,#1122,#1134,#1146,#1158,#1170,#1182,#1194,#1206,#1218,#1230,#1242,#1254,#1266,#1278,
#1290,#1302,#1314,#1326,#1338,#1350,#1362,#1374,#1386,#1398,#1410,#1422,#1434,#1446,#1458));
#1460=MANIFOLD_SOLID_BREP('B2',#1459);
#1461=ADVANCED_BREP_SHAPE_REPRESENTATION('',(#18,#1460),#14);
#1462=SHAPE_DEFINITION_REPRESENTATION(#9,#1461);
ENDSEC;
END-ISO-10303-21;
